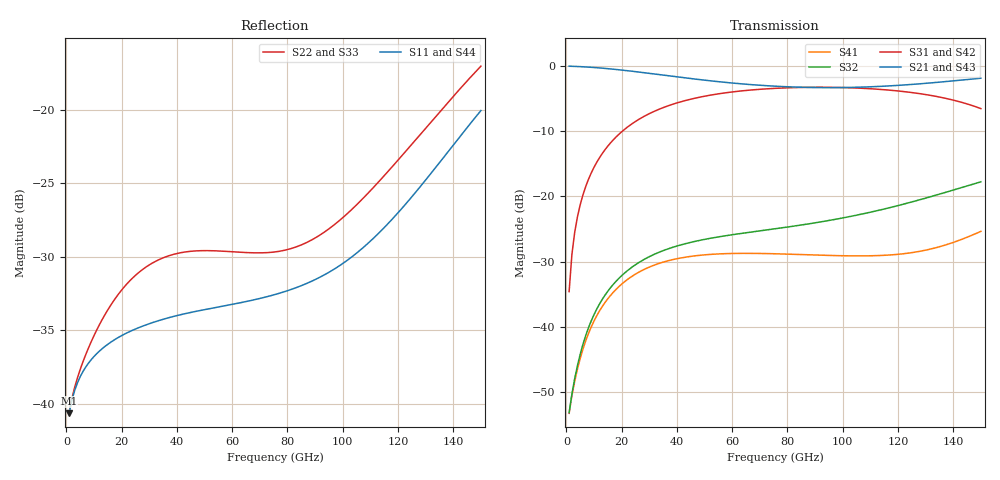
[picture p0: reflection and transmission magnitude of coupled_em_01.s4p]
! EM-extracted passive device data (anonymized for regression tests)
# Hz S RI R 50
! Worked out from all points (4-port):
!   150 points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, 1 GHz to 150 GHz, reference 50 ohm
!   strongest paths, dB at 1 GHz, 38 GHz, 76 GHz, 113 GHz, 150 GHz:
!     S21: -0.1, -1.6, -3.2, -3.2, -1.9
!     S43: -0.1, -1.6, -3.2, -3.2, -1.9
!     S31: -34.6, -6.0, -3.5, -3.6, -6.6
!     S42: -34.6, -6.0, -3.5, -3.6, -6.6
!     S32: -53.1, -27.9, -24.9, -22.1, -17.8
!     S41: -53.2, -29.7, -28.8, -29.1, -25.4
!   lowest |S11| = -40.7 dB at 1 GHz (marker M1), VSWR 1.02, Z = 50.9 + j0.125 ohm
!   |S11| at or under -10 dB: start of sweep to end of sweep
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1e9  0.0092 0.00123  0.9902 -0.0283  0.0026 0.0185  -0.00214 -0.000487
     0.9902 -0.0283  0.00923 0.00123  -0.00216 -0.00049  0.0026 0.0185
     0.0026 0.0185  -0.00216 -0.00049  0.00922 0.00123  0.9902 -0.0283
     -0.00214 -0.000487  0.0026 0.0185  0.9902 -0.0283  0.00919 0.00122
4e9  0.0117 -0.000781  0.9792 -0.1064  0.0113 0.0686  -0.00362 0.00309
     0.9792 -0.1064  0.0122 -0.000876  -0.00395 0.00317  0.0113 0.0686
     0.0113 0.0686  -0.00395 0.00317  0.0122 -0.000877  0.9792 -0.1064
     -0.00362 0.00309  0.0113 0.0686  0.9792 -0.1064  0.0117 -0.000785
9e9  0.0124 -0.00675  0.9442 -0.2274  0.0402 0.1455  -0.00178 0.00986
     0.9442 -0.2274  0.0143 -0.00776  -0.00304 0.0107  0.0402 0.1455
     0.0402 0.1455  -0.00304 0.0107  0.0143 -0.00776  0.9442 -0.2274
     -0.00178 0.00986  0.0402 0.1455  0.9442 -0.2274  0.0124 -0.00673
1.8e10  0.00506 -0.0159  0.8399 -0.4104  0.1301 0.2532  0.00914 0.0172
        0.8399 -0.4104  0.00971 -0.0209  0.0066 0.0214  0.1301 0.2532
        0.1301 0.2532  0.0066 0.0214  0.00974 -0.0209  0.8399 -0.4104
        0.00914 0.0172  0.1301 0.2532  0.8399 -0.4104  0.00503 -0.0158
3.2e10  -0.0122 -0.0146  0.6257 -0.5936  0.3129 0.3222  0.0281 0.0102
        0.6257 -0.5936  -0.00603 -0.0298  0.0282 0.0227  0.3129 0.3222
        0.3129 0.3222  0.0282 0.0227  -0.00596 -0.0299  0.6257 -0.5937
        0.0281 0.0102  0.3129 0.3222  0.6257 -0.5937  -0.0122 -0.0145
8.8e10  -0.00912 0.0243  -0.0514 -0.679  0.6815 -0.0407  -0.00452 -0.0354
        -0.0514 -0.679  -0.0214 -0.0287  0.0481 -0.0387  0.6815 -0.0406
        0.6815 -0.0407  0.0481 -0.0387  -0.0214 -0.029  -0.0515 -0.679
        -0.00452 -0.0354  0.6815 -0.0406  -0.0515 -0.679  -0.00904 0.0246
1.5e11  0.0618 0.0781  -0.6861 -0.4139  0.2874 -0.3706  -0.00422 0.0538
        -0.6861 -0.4139  -0.1043 -0.095  -0.0492 -0.1195  0.2874 -0.3706
        0.2874 -0.3706  -0.0492 -0.1195  -0.1048 -0.0954  -0.6861 -0.4137
        -0.00422 0.0538  0.2874 -0.3706  -0.6861 -0.4137  0.0624 0.0783
